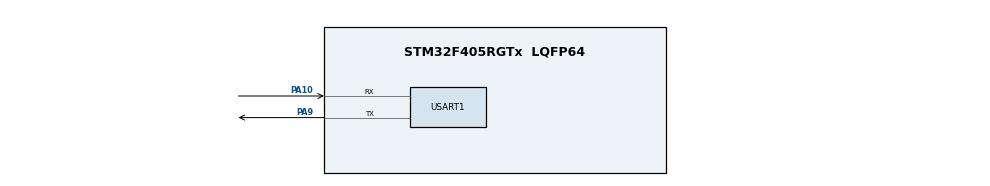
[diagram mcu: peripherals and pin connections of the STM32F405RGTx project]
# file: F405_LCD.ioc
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Mcu.Family=STM32F4
Mcu.Name=STM32F405RGTx
Mcu.Package=LQFP64
NVIC.PriorityGroup=NVIC_PRIORITYGROUP_4
PA10.Mode=Asynchronous
PA10.Signal=USART1_RX
PA13.Mode=Serial_Wire
PA13.Signal=SYS_JTMS-SWDIO
PA14.Mode=Serial_Wire
PA14.Signal=SYS_JTCK-SWCLK
PA9.Mode=Asynchronous
PA9.Signal=USART1_TX
PC14-OSC32_IN.Mode=LSE-External-Oscillator
PC14-OSC32_IN.Signal=RCC_OSC32_IN
PC15-OSC32_OUT.Mode=LSE-External-Oscillator
PC15-OSC32_OUT.Signal=RCC_OSC32_OUT
PH0-OSC_IN.Mode=HSE-External-Oscillator
PH0-OSC_IN.Signal=RCC_OSC_IN
PH1-OSC_OUT.Mode=HSE-External-Oscillator
PH1-OSC_OUT.Signal=RCC_OSC_OUT
ProjectManager.HeapSize=0x200
ProjectManager.StackSize=0x400
ProjectManager.TargetToolchain=STM32CubeIDE
RCC.48MHZClocksFreq_Value=84000000
RCC.AHBFreq_Value=168000000
RCC.APB1CLKDivider=RCC_HCLK_DIV4
RCC.APB1Freq_Value=42000000
RCC.APB1TimFreq_Value=84000000
RCC.APB2CLKDivider=RCC_HCLK_DIV2
RCC.APB2Freq_Value=84000000
RCC.APB2TimFreq_Value=168000000
RCC.CortexFreq_Value=168000000
RCC.HCLKFreq_Value=168000000
RCC.HSE_VALUE=25000000
RCC.HSI_VALUE=16000000
RCC.PLLM=8
RCC.PLLN=168
RCC.SYSCLKFreq_VALUE=168000000
RCC.SYSCLKSource=RCC_SYSCLKSOURCE_PLLCLK
RCC.VCOOutputFreq_Value=336000000
USART1.VirtualMode=VM_ASYNC
VP_RTC_VS_RTC_Activate.Mode=RTC_Enabled
VP_RTC_VS_RTC_Calendar.Mode=RTC_Calendar
board=custom

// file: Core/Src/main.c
/* USER CODE BEGIN Header */
/**
  ******************************************************************************
  * @file           : main.c
  * @brief          : Main program body
  ******************************************************************************
  * @attention
  *
  * Copyright (c) 2023 STMicroelectronics.
  * All rights reserved.
  *
  * This software is licensed under terms that can be found in the LICENSE file
  * in the root directory of this software component.
  * If no LICENSE file comes with this software, it is provided AS-IS.
  *
  ******************************************************************************
  */
/* USER CODE END Header */
#include "main.h"
#include "rtc.h"
#include "usart.h"
#include "gpio.h"

/* USER CODE BEGIN Includes */
#include "board.h"
#include <stdio.h>
/* USER CODE END Includes */

/* USER CODE BEGIN PD */
#ifdef __GNUC__
  /* With GCC, small printf (option LD Linker->Libraries->Small printf
     set to 'Yes') calls __io_putchar() */
int __io_putchar(int ch)
#else
int fputc(int ch, FILE *f)
#endif /* __GNUC__ */
{
  /* Place your implementation of fputc here */
  /* e.g. write a character to the UART1 and Loop until the end of transmission */
  HAL_UART_Transmit(&huart1, (uint8_t *)&ch, 1, HAL_MAX_DELAY);

  return ch;
}
/* USER CODE END PD */

void SystemClock_Config(void);

int main(void)
{

  /* MCU Configuration--------------------------------------------------------*/

  /* Reset of all peripherals, Initializes the Flash interface and the Systick. */
  HAL_Init();

  /* Configure the system clock */
  SystemClock_Config();

  /* Initialize all configured peripherals */
  MX_GPIO_Init();
  MX_RTC_Init();
  MX_USART1_UART_Init();
  /* USER CODE BEGIN 2 */
  board_button_init();

  board_led_init();

  uint32_t tick,tick_now;
  tick = HAL_GetTick() + 200;
  tick_now = HAL_GetTick();
  /* USER CODE END 2 */

  /* Infinite loop */
  /* USER CODE BEGIN WHILE */
  while (1)
  {
    tick_now = HAL_GetTick();
    if(board_button_getstate())
    {
      if(tick_now >= tick)
      {
        tick = tick_now + 200;
        board_led_toggle();
      }
    }
    else
    {
      if(tick_now >= tick)
      {
        tick = tick_now + 50;

        RTC_DateTypeDef sdatestructureget;
        RTC_TimeTypeDef stimestructureget;
        uint8_t text[30];
        static uint8_t Seconds_o;

        /* Get the RTC current Time */
        HAL_RTC_GetTime(&hrtc, &stimestructureget, RTC_FORMAT_BIN);
        /* Get the RTC current Date */
        HAL_RTC_GetDate(&hrtc, &sdatestructureget, RTC_FORMAT_BIN);

        if(Seconds_o != stimestructureget.Seconds)
        {
          Seconds_o = stimestructureget.Seconds;
          char msg[] = "RTC initialized successfully.\n";
          HAL_UART_Transmit(&huart1, (uint8_t*)msg, sizeof(msg)-1, HAL_MAX_DELAY);
          /*
          printf("Y20%02d.M%02d.D%02d %02d:%02d:%02d\r\n",
                  sdatestructureget.Year,
                  sdatestructureget.Month,
                  sdatestructureget.Date,
                  stimestructureget.Hours,
                  stimestructureget.Minutes,
                  stimestructureget.Seconds);
          */
          board_led_set(1);
        }
        else
        {
          board_led_set(0);
        }
      }
    }
    /* USER CODE END WHILE */

  }
}

void SystemClock_Config(void)
{
  RCC_OscInitTypeDef RCC_OscInitStruct = {0};
  RCC_ClkInitTypeDef RCC_ClkInitStruct = {0};

  /** Configure the main internal regulator output voltage
  */
  __HAL_RCC_PWR_CLK_ENABLE();
  __HAL_PWR_VOLTAGESCALING_CONFIG(PWR_REGULATOR_VOLTAGE_SCALE1);

  /** Initializes the RCC Oscillators according to the specified parameters
  * in the RCC_OscInitTypeDef structure.
  */
  RCC_OscInitStruct.OscillatorType = RCC_OSCILLATORTYPE_HSE|RCC_OSCILLATORTYPE_LSE;
  RCC_OscInitStruct.HSEState = RCC_HSE_ON;
  RCC_OscInitStruct.LSEState = RCC_LSE_ON;
  RCC_OscInitStruct.PLL.PLLState = RCC_PLL_ON;
  RCC_OscInitStruct.PLL.PLLSource = RCC_PLLSOURCE_HSE;
  RCC_OscInitStruct.PLL.PLLM = 4;
  RCC_OscInitStruct.PLL.PLLN = 168;
  RCC_OscInitStruct.PLL.PLLP = RCC_PLLP_DIV2;
  RCC_OscInitStruct.PLL.PLLQ = 4;
  if (HAL_RCC_OscConfig(&RCC_OscInitStruct) != HAL_OK)
  {
    Error_Handler();
  }

  /** Initializes the CPU, AHB and APB buses clocks
  */
  RCC_ClkInitStruct.ClockType = RCC_CLOCKTYPE_HCLK|RCC_CLOCKTYPE_SYSCLK
                              |RCC_CLOCKTYPE_PCLK1|RCC_CLOCKTYPE_PCLK2;
  RCC_ClkInitStruct.SYSCLKSource = RCC_SYSCLKSOURCE_PLLCLK;
  RCC_ClkInitStruct.AHBCLKDivider = RCC_SYSCLK_DIV1;
  RCC_ClkInitStruct.APB1CLKDivider = RCC_HCLK_DIV4;
  RCC_ClkInitStruct.APB2CLKDivider = RCC_HCLK_DIV2;

  if (HAL_RCC_ClockConfig(&RCC_ClkInitStruct, FLASH_LATENCY_5) != HAL_OK)
  {
    Error_Handler();
  }
}

void Error_Handler(void)
{
  __disable_irq();
  while (1)
  {
  }
}
